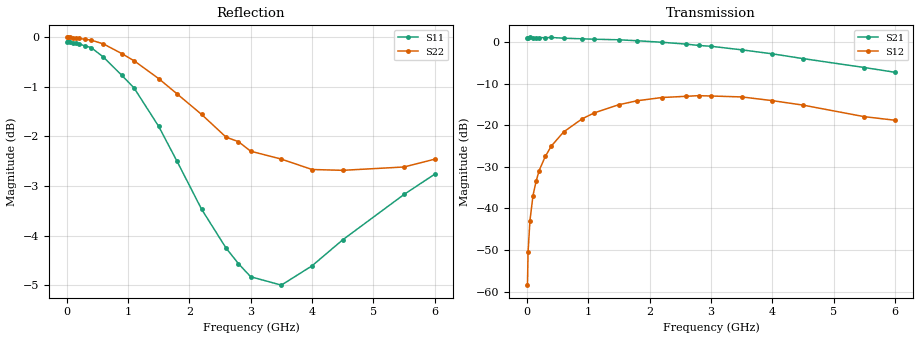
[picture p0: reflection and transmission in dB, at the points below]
! SIEMENS Small Signal Semiconductors
! BFP181
! Si NPN RF Bipolar Junction Transistor in SOT143
! VCE = 3.5 V  IC = 0.3 mA
! Common Emitter S-Parameters:  March  1996
# GHz  S  MA  R  50
!  f  S11  S21  S12  S22
! GHz  MAG  ANG  MAG  ANG  MAG  ANG  MAG  ANG
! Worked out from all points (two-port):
!   36 points, 10 MHz to 6 GHz, reference 50 ohm
!   highest |S21| = 1.09 dB at 50 MHz (marker M1); lowest = -7.3 dB at 6 GHz (marker M2)
!   |S21| within 3 dB of the highest: start of sweep to 3.507 GHz
!   lowest |S11| = -5.0 dB at 3.5 GHz (marker M3), VSWR 3.57, Z = 14.1 + j4.84 ohm
!   |S11| at or under -10 dB: nowhere
!   |S22| runs from -2.7 to 0.0 dB; largest |S21 - S12| = 1.1
!   S11 on the Smith chart (normalised r, x): 10 MHz: open; 900 MHz: 0.32, -2.48; 1.8 GHz: 0.28, -0.96; 2.8 GHz: 0.27, -0.26; 4 GHz: 0.28, +0.30; 6 GHz: 0.31, +0.97
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0.01  0.9873 -0.6  1.113 179.9  0.0012 92.8  0.9986 -0.2
0.02  0.9892 -1.1  1.129 179.8  0.003 88.9  0.9984 -0.5
0.05  0.9889 -2.1  1.134 177.8  0.0071 89.8  0.9985 -1.2
0.1  0.9863 -4.9  1.111 175.0  0.0143 86.9  0.9975 -2.4
0.15  0.9859 -7.4  1.129 172.4  0.0211 84.7  0.9969 -3.5
0.2  0.9837 -9.5  1.127 169.8  0.0285 82.7  0.9965 -4.8
0.3  0.9792 -14.3  1.126 165.6  0.0421 79.3  0.9941 -7.2
0.4  0.9752 -19.0  1.131 159.7  0.0563 75.9  0.9923 -9.6
0.6  0.9541 -28.5  1.109 150.0  0.0831 68.4  0.9836 -14.3
0.9  0.9146 -43.3  1.09 135.5  0.1191 58.0  0.9618 -21.1
1.1  0.8881 -53.0  1.078 126.5  0.1407 51.3  0.9459 -25.4
1.5  0.8128 -73.7  1.061 108.7  0.1763 38.4  0.9078 -33.8
1.8  0.7495 -89.8  1.033 94.8  0.1967 29.8  0.8762 -39.4
2.2  0.6709 -112.5  0.991 77.8  0.2149 18.3  0.8355 -46.7
2.6  0.613 -137.3  0.941 62.6  0.2224 8.1  0.7926 -53.3
2.8  0.5915 -149.3  0.907 54.4  0.2263 2.8  0.7845 -56.6
3  0.5738 -162.1  0.887 46.8  0.2242 -2.2  0.7673 -60.0
3.5  0.5628 168.0  0.804 29.6  0.2186 -13.0  0.7534 -68.2
4  0.5885 143.9  0.72 14.3  0.1973 -22.1  0.7355 -77.7
4.5  0.625 124.8  0.631 1.1  0.1743 -29.3  0.7341 -88.2
5.5  0.6942 98.2  0.493 -18.7  0.1266 -30.2  0.7398 -110.0
6  0.7276 89.0  0.432 -25.9  0.1147 -25.3  0.7533 -121.2
